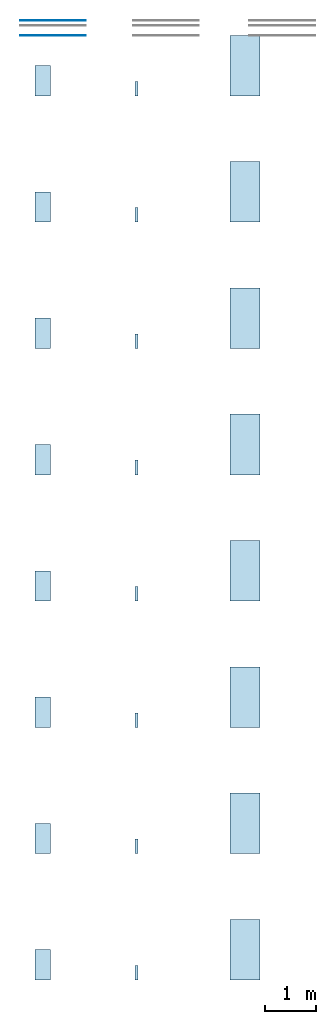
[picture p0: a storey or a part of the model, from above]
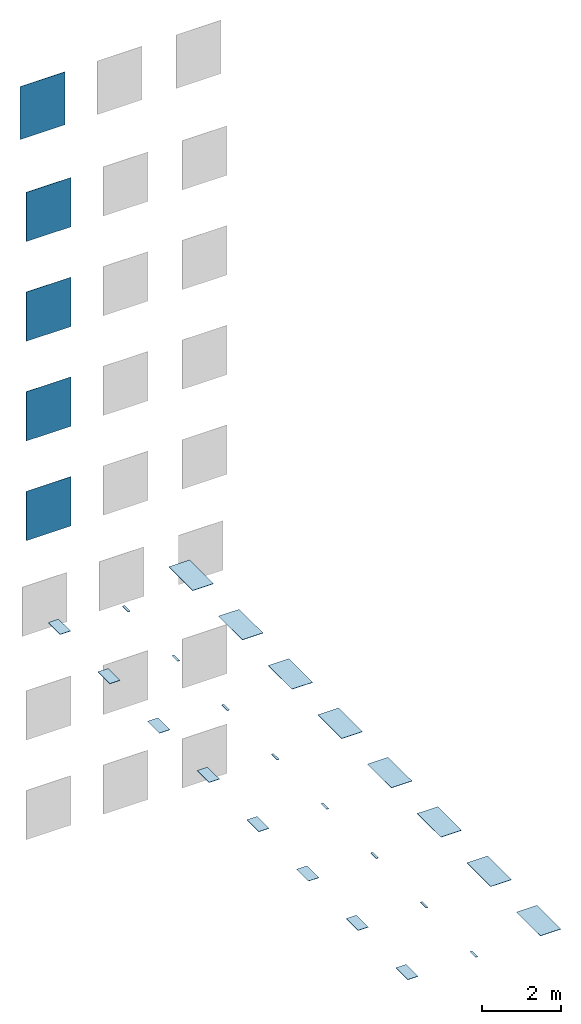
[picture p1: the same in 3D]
Properties of the parts of a building model (IFC2X3)

# File
Description: ViewDefinition [CoordinationView_V2.0], RevitIdentifiers [VersionGUID: be6d3f83-cdeb-4463-9c20-2c39ddd38491, NumberOfSaves: 313], CoordinateReference [CoordinateBase: Shared Coordinates, ProjectSite: Internal]
File name: Project Number
Time: 2025-01-29T16:04:23+01:00
Written by: ODA SDAI 24.3
Made in: Autodesk Revit 24.1.11.26 (ENU) - IFC 24.1.11.26

# IfcProject, Project Number
LongName: Refin-Blended; Phase: Project Status

# IfcSite, Default
RefLatitude: 51, 30, 0, 549316; RefLongitude: 0, -7, -34, -450321; RefElevation: 0 mm

# IfcBuilding
Pset_BuildingCommon - NumberOfStoreys: 1

# IfcBuildingStorey: Level:Circle Head - Project Datum (2)
Pset_AirSideSystemInformation - sets with these values: 2
Name | LongName = Name | Elevation (mm)
Level 0 | Level 0 | 0
Level 1 | Level 1 | 4000

# IfcSlab: Floor:Floor_Tiles_Refin-Upside-Black-30x60 RK33, Floor:Floor_Tiles_Refin-Upside-Black-30x60 RK33:304668
In: Level 0
Type - PredefinedType: FLOOR; Material: Upside-Black-30x60 RK33 9 mm, <Unnamed> 1 mm
Type - Pset_ConcreteElementGeneral - FireRating: INERT
Type - Pset_ElementShading - Color: BLACK
Type - Pset_FireRatingProperties - SurfaceSpreadOfFlame: INERT
Type - Pset_ManufacturerOccurrence - BarCode: N/A; SerialNumber: N/A
Type - Pset_ManufacturerTypeInformation - ArticleNumber: RK33; ModelReference: RK33; ModelLabel: BLACK R 30X60; Manufacturer: info@refin.it; ProductionYear: N/A
Type - Pset_PrecastConcreteElementGeneral - SerialNumber: N/A
Type - Pset_ProductRequirements - Name: Upside_Black_30X60 R; Category: Pr_35_93_96_19:Ceramic tiles
Type - Pset_QuantityTakeOff - Reference: N/A
Type - Pset_ReinforcementBarPitchOfSlab - Description: PORCELAIN STONEWARE TILE; Reference: N/A
Type - Pset_SlabCommon - Reference: N/A; IsExternal: no; AcousticRating: N/A; FireRating: INERT; SurfaceSpreadOfFlame: INERT
Type - Pset_Warranty - WarrantyContent: N/A; Exclusions: N/A
Pset_QuantityTakeOff - sets with these values: 2
Pset_SlabCommon - LoadBearing: no; PitchAngle: 0 deg

# IfcSlab: Floor:Floor_Tiles_Refin-Upside-Black-6,3x29 RK41, Floor:Floor_Tiles_Refin-Upside-Black-6,3x29 RK41:350442
In: Level 0
Type - PredefinedType: FLOOR; Material: Upside-Black-6,3x29 RK41 9 mm, <Unnamed> 1 mm
Type - Pset_ConcreteElementGeneral - FireRating: INERT
Type - Pset_ElementShading - Color: BLACK
Type - Pset_FireRatingProperties - SurfaceSpreadOfFlame: INERT
Type - Pset_ManufacturerOccurrence - BarCode: N/A; SerialNumber: N/A
Type - Pset_ManufacturerTypeInformation - ArticleNumber: RK41; ModelReference: RK41; ModelLabel: BLACK R 6,3X29; Manufacturer: info@refin.it; ProductionYear: N/A
Type - Pset_PrecastConcreteElementGeneral - SerialNumber: N/A
Type - Pset_ProductRequirements - Name: Upside_Black_6,3X29 R; Category: Pr_35_93_96_19:Ceramic tiles
Type - Pset_QuantityTakeOff - Reference: N/A
Type - Pset_ReinforcementBarPitchOfSlab - Description: PORCELAIN STONEWARE TILE; Reference: N/A
Type - Pset_SlabCommon - Reference: N/A; IsExternal: no; AcousticRating: N/A; FireRating: INERT; SurfaceSpreadOfFlame: INERT
Type - Pset_Warranty - WarrantyContent: N/A; Exclusions: N/A
Pset_QuantityTakeOff - sets with these values: 2
Pset_SlabCommon - LoadBearing: no; PitchAngle: 0 deg

# IfcSlab: Floor:Floor_Tiles_Refin-Upside-Black-60x120 RK25, Floor:Floor_Tiles_Refin-Upside-Black-60x120 RK25:350624
In: Level 0
Type - PredefinedType: FLOOR; Material: Upside-Black-60x120 RK25 9 mm, <Unnamed> 1 mm
Type - Pset_ConcreteElementGeneral - FireRating: INERT
Type - Pset_ElementShading - Color: BLACK
Type - Pset_FireRatingProperties - SurfaceSpreadOfFlame: INERT
Type - Pset_ManufacturerOccurrence - BarCode: N/A; SerialNumber: N/A
Type - Pset_ManufacturerTypeInformation - ArticleNumber: RK25; ModelReference: RK25; ModelLabel: BLACK R 60X120; Manufacturer: info@refin.it; ProductionYear: N/A
Type - Pset_PrecastConcreteElementGeneral - SerialNumber: N/A
Type - Pset_ProductRequirements - Name: Upside_Black_60X120 R; Category: Pr_35_93_96_19:Ceramic tiles
Type - Pset_QuantityTakeOff - Reference: N/A
Type - Pset_ReinforcementBarPitchOfSlab - Description: PORCELAIN STONEWARE TILE; Reference: N/A
Type - Pset_SlabCommon - Reference: N/A; IsExternal: no; AcousticRating: N/A; FireRating: INERT; SurfaceSpreadOfFlame: INERT
Type - Pset_Warranty - WarrantyContent: N/A; Exclusions: N/A
Pset_QuantityTakeOff - sets with these values: 2
Pset_SlabCommon - LoadBearing: no; PitchAngle: 0 deg

# IfcSlab: Floor:Floor_Tiles_Refin-Upside-Blue-30x60 RK34, Floor:Floor_Tiles_Refin-Upside-Blue-30x60 RK34:351193
In: Level 0
Type - PredefinedType: FLOOR; Material: Upside-Blue-30x60 RK34 9 mm, <Unnamed> 1 mm
Type - Pset_ConcreteElementGeneral - FireRating: INERT
Type - Pset_ElementShading - Color: BLUE
Type - Pset_FireRatingProperties - SurfaceSpreadOfFlame: INERT
Type - Pset_ManufacturerOccurrence - BarCode: N/A; SerialNumber: N/A
Type - Pset_ManufacturerTypeInformation - ArticleNumber: RK34; ModelReference: RK34; ModelLabel: BLUE R 30X60; Manufacturer: info@refin.it; ProductionYear: N/A
Type - Pset_PrecastConcreteElementGeneral - SerialNumber: N/A
Type - Pset_ProductRequirements - Name: Upside_Blue_30X60 R; Category: Pr_35_93_96_19:Ceramic tiles
Type - Pset_QuantityTakeOff - Reference: N/A
Type - Pset_ReinforcementBarPitchOfSlab - Description: PORCELAIN STONEWARE TILE; Reference: N/A
Type - Pset_SlabCommon - Reference: N/A; IsExternal: no; AcousticRating: N/A; FireRating: INERT; SurfaceSpreadOfFlame: INERT
Type - Pset_Warranty - WarrantyContent: N/A; Exclusions: N/A
Pset_QuantityTakeOff - sets with these values: 2
Pset_SlabCommon - LoadBearing: no; PitchAngle: 0 deg

# IfcSlab: Floor:Floor_Tiles_Refin-Upside-Blue-6,3x29 RK42, Floor:Floor_Tiles_Refin-Upside-Blue-6,3x29 RK42:351201
In: Level 0
Type - PredefinedType: FLOOR; Material: Upside-Blue-6,3x29 RK42 9 mm, <Unnamed> 1 mm
Type - Pset_ConcreteElementGeneral - FireRating: INERT
Type - Pset_ElementShading - Color: BLUE
Type - Pset_FireRatingProperties - SurfaceSpreadOfFlame: INERT
Type - Pset_ManufacturerOccurrence - BarCode: N/A; SerialNumber: N/A
Type - Pset_ManufacturerTypeInformation - ArticleNumber: RK42; ModelReference: RK42; ModelLabel: BLUE R 6,3X29; Manufacturer: info@refin.it; ProductionYear: N/A
Type - Pset_PrecastConcreteElementGeneral - SerialNumber: N/A
Type - Pset_ProductRequirements - Name: Upside_Blue_6,3X29 R; Category: Pr_35_93_96_19:Ceramic tiles
Type - Pset_QuantityTakeOff - Reference: N/A
Type - Pset_ReinforcementBarPitchOfSlab - Description: PORCELAIN STONEWARE TILE; Reference: N/A
Type - Pset_SlabCommon - Reference: N/A; IsExternal: no; AcousticRating: N/A; FireRating: INERT; SurfaceSpreadOfFlame: INERT
Type - Pset_Warranty - WarrantyContent: N/A; Exclusions: N/A
Pset_QuantityTakeOff - sets with these values: 2
Pset_SlabCommon - LoadBearing: no; PitchAngle: 0 deg

# IfcSlab: Floor:Floor_Tiles_Refin-Upside-Blue-60x120 RK26, Floor:Floor_Tiles_Refin-Upside-Blue-60x120 RK26:351209
In: Level 0
Type - PredefinedType: FLOOR; Material: Upside-Blue-60x120 RK26 9 mm, <Unnamed> 1 mm
Type - Pset_ConcreteElementGeneral - FireRating: INERT
Type - Pset_ElementShading - Color: BLUE
Type - Pset_FireRatingProperties - SurfaceSpreadOfFlame: INERT
Type - Pset_ManufacturerOccurrence - BarCode: N/A; SerialNumber: N/A
Type - Pset_ManufacturerTypeInformation - ArticleNumber: RK26; ModelReference: RK26; ModelLabel: BLUE R 60X120; Manufacturer: info@refin.it; ProductionYear: N/A
Type - Pset_PrecastConcreteElementGeneral - SerialNumber: N/A
Type - Pset_ProductRequirements - Name: Upside_Blue_60X120 R; Category: Pr_35_93_96_19:Ceramic tiles
Type - Pset_QuantityTakeOff - Reference: N/A
Type - Pset_ReinforcementBarPitchOfSlab - Description: PORCELAIN STONEWARE TILE; Reference: N/A
Type - Pset_SlabCommon - Reference: N/A; IsExternal: no; AcousticRating: N/A; FireRating: INERT; SurfaceSpreadOfFlame: INERT
Type - Pset_Warranty - WarrantyContent: N/A; Exclusions: N/A
Pset_QuantityTakeOff - sets with these values: 2
Pset_SlabCommon - LoadBearing: no; PitchAngle: 0 deg

# IfcSlab: Floor:Floor_Tiles_Refin-Upside-Green-30x60 RK35, Floor:Floor_Tiles_Refin-Upside-Green-30x60 RK35:351773
In: Level 0
Type - PredefinedType: FLOOR; Material: Upside-Green-30x60 RK35 9 mm, <Unnamed> 1 mm
Type - Pset_ConcreteElementGeneral - FireRating: INERT
Type - Pset_ElementShading - Color: GREEN
Type - Pset_FireRatingProperties - SurfaceSpreadOfFlame: INERT
Type - Pset_ManufacturerOccurrence - BarCode: N/A; SerialNumber: N/A
Type - Pset_ManufacturerTypeInformation - ArticleNumber: RK35; ModelReference: RK35; ModelLabel: GREEN R 30X60; Manufacturer: info@refin.it; ProductionYear: N/A
Type - Pset_PrecastConcreteElementGeneral - SerialNumber: N/A
Type - Pset_ProductRequirements - Name: Upside_Green_30X60 R; Category: Pr_35_93_96_19:Ceramic tiles
Type - Pset_QuantityTakeOff - Reference: N/A
Type - Pset_ReinforcementBarPitchOfSlab - Description: PORCELAIN STONEWARE TILE; Reference: N/A
Type - Pset_SlabCommon - Reference: N/A; IsExternal: no; AcousticRating: N/A; FireRating: INERT; SurfaceSpreadOfFlame: INERT
Type - Pset_Warranty - WarrantyContent: N/A; Exclusions: N/A
Pset_QuantityTakeOff - sets with these values: 2
Pset_SlabCommon - LoadBearing: no; PitchAngle: 0 deg

# IfcSlab: Floor:Floor_Tiles_Refin-Upside-Green-6,3x29 RK43, Floor:Floor_Tiles_Refin-Upside-Green-6,3x29 RK43:351781
In: Level 0
Type - PredefinedType: FLOOR; Material: Upside-Green-6,3x29 RK43 9 mm, <Unnamed> 1 mm
Type - Pset_ConcreteElementGeneral - FireRating: INERT
Type - Pset_ElementShading - Color: GREEN
Type - Pset_FireRatingProperties - SurfaceSpreadOfFlame: INERT
Type - Pset_ManufacturerOccurrence - BarCode: N/A; SerialNumber: N/A
Type - Pset_ManufacturerTypeInformation - ArticleNumber: RK43; ModelReference: RK43; ModelLabel: GREEN R 6,3X29; Manufacturer: info@refin.it; ProductionYear: N/A
Type - Pset_PrecastConcreteElementGeneral - SerialNumber: N/A
Type - Pset_ProductRequirements - Name: Upside_Green_6,3X29 R; Category: Pr_35_93_96_19:Ceramic tiles
Type - Pset_QuantityTakeOff - Reference: N/A
Type - Pset_ReinforcementBarPitchOfSlab - Description: PORCELAIN STONEWARE TILE; Reference: N/A
Type - Pset_SlabCommon - Reference: N/A; IsExternal: no; AcousticRating: N/A; FireRating: INERT; SurfaceSpreadOfFlame: INERT
Type - Pset_Warranty - WarrantyContent: N/A; Exclusions: N/A
Pset_QuantityTakeOff - sets with these values: 2
Pset_SlabCommon - LoadBearing: no; PitchAngle: 0 deg

# IfcSlab: Floor:Floor_Tiles_Refin-Upside-Green-60x120 RK27, Floor:Floor_Tiles_Refin-Upside-Green-60x120 RK27:351789
In: Level 0
Type - PredefinedType: FLOOR; Material: Upside-Green-60x120 RK27 9 mm, <Unnamed> 1 mm
Type - Pset_ConcreteElementGeneral - FireRating: INERT
Type - Pset_ElementShading - Color: GREEN
Type - Pset_FireRatingProperties - SurfaceSpreadOfFlame: INERT
Type - Pset_ManufacturerOccurrence - BarCode: N/A; SerialNumber: N/A
Type - Pset_ManufacturerTypeInformation - ArticleNumber: RK27; ModelReference: RK27; ModelLabel: GREEN R 60X120; Manufacturer: info@refin.it; ProductionYear: N/A
Type - Pset_PrecastConcreteElementGeneral - SerialNumber: N/A
Type - Pset_ProductRequirements - Name: Upside_Green_60X120 R; Category: Pr_35_93_96_19:Ceramic tiles
Type - Pset_QuantityTakeOff - Reference: N/A
Type - Pset_ReinforcementBarPitchOfSlab - Description: PORCELAIN STONEWARE TILE; Reference: N/A
Type - Pset_SlabCommon - Reference: N/A; IsExternal: no; AcousticRating: N/A; FireRating: INERT; SurfaceSpreadOfFlame: INERT
Type - Pset_Warranty - WarrantyContent: N/A; Exclusions: N/A
Pset_QuantityTakeOff - sets with these values: 2
Pset_SlabCommon - LoadBearing: no; PitchAngle: 0 deg

# IfcSlab: Floor:Floor_Tiles_Refin-Upside-Pink-30x60 RK37, Floor:Floor_Tiles_Refin-Upside-Pink-30x60 RK37:352848
In: Level 0
Type - PredefinedType: FLOOR; Material: Upside-Pink-30x60 RK37 9 mm, <Unnamed> 1 mm
Type - Pset_ConcreteElementGeneral - FireRating: INERT
Type - Pset_ElementShading - Color: PINK
Type - Pset_FireRatingProperties - SurfaceSpreadOfFlame: INERT
Type - Pset_ManufacturerOccurrence - BarCode: N/A; SerialNumber: N/A
Type - Pset_ManufacturerTypeInformation - ArticleNumber: RK37; ModelReference: RK37; ModelLabel: PINK R 30X60; Manufacturer: info@refin.it; ProductionYear: N/A
Type - Pset_PrecastConcreteElementGeneral - SerialNumber: N/A
Type - Pset_ProductRequirements - Name: Upside_Pink_30X60 R; Category: Pr_35_93_96_19:Ceramic tiles
Type - Pset_QuantityTakeOff - Reference: N/A
Type - Pset_ReinforcementBarPitchOfSlab - Description: PORCELAIN STONEWARE TILE; Reference: N/A
Type - Pset_SlabCommon - Reference: N/A; IsExternal: no; AcousticRating: N/A; FireRating: INERT; SurfaceSpreadOfFlame: INERT
Type - Pset_Warranty - WarrantyContent: N/A; Exclusions: N/A
Pset_QuantityTakeOff - sets with these values: 2
Pset_SlabCommon - LoadBearing: no; PitchAngle: 0 deg

# IfcSlab: Floor:Floor_Tiles_Refin-Upside-Pink-6,3x29 RK45, Floor:Floor_Tiles_Refin-Upside-Pink-6,3x29 RK45:352856
In: Level 0
Type - PredefinedType: FLOOR; Material: Upside-Pink-6,3x29 RK45 9 mm, <Unnamed> 1 mm
Type - Pset_ConcreteElementGeneral - FireRating: INERT
Type - Pset_ElementShading - Color: PINK
Type - Pset_FireRatingProperties - SurfaceSpreadOfFlame: INERT
Type - Pset_ManufacturerOccurrence - BarCode: N/A; SerialNumber: N/A
Type - Pset_ManufacturerTypeInformation - ArticleNumber: RK45; ModelReference: RK45; ModelLabel: PINK R 6,3X29; Manufacturer: info@refin.it; ProductionYear: N/A
Type - Pset_PrecastConcreteElementGeneral - SerialNumber: N/A
Type - Pset_ProductRequirements - Name: Upside_Pink_6,3X29 R; Category: Pr_35_93_96_19:Ceramic tiles
Type - Pset_QuantityTakeOff - Reference: N/A
Type - Pset_ReinforcementBarPitchOfSlab - Description: PORCELAIN STONEWARE TILE; Reference: N/A
Type - Pset_SlabCommon - Reference: N/A; IsExternal: no; AcousticRating: N/A; FireRating: INERT; SurfaceSpreadOfFlame: INERT
Type - Pset_Warranty - WarrantyContent: N/A; Exclusions: N/A
Pset_QuantityTakeOff - sets with these values: 2
Pset_SlabCommon - LoadBearing: no; PitchAngle: 0 deg

# IfcSlab: Floor:Floor_Tiles_Refin-Upside-Pink-60x120 RK29, Floor:Floor_Tiles_Refin-Upside-Pink-60x120 RK29:352863
In: Level 0
Type - PredefinedType: FLOOR; Material: Upside-Pink-60x120 RK29 9 mm, <Unnamed> 1 mm
Type - Pset_ConcreteElementGeneral - FireRating: INERT
Type - Pset_ElementShading - Color: PINK
Type - Pset_FireRatingProperties - SurfaceSpreadOfFlame: INERT
Type - Pset_ManufacturerOccurrence - BarCode: N/A; SerialNumber: N/A
Type - Pset_ManufacturerTypeInformation - ArticleNumber: RK29; ModelReference: RK29; ModelLabel: PINK R 60X120; Manufacturer: info@refin.it; ProductionYear: N/A
Type - Pset_PrecastConcreteElementGeneral - SerialNumber: N/A
Type - Pset_ProductRequirements - Name: Upside_Pink_60X120 R; Category: Pr_35_93_96_19:Ceramic tiles
Type - Pset_QuantityTakeOff - Reference: N/A
Type - Pset_ReinforcementBarPitchOfSlab - Description: PORCELAIN STONEWARE TILE; Reference: N/A
Type - Pset_SlabCommon - Reference: N/A; IsExternal: no; AcousticRating: N/A; FireRating: INERT; SurfaceSpreadOfFlame: INERT
Type - Pset_Warranty - WarrantyContent: N/A; Exclusions: N/A
Pset_QuantityTakeOff - sets with these values: 2
Pset_SlabCommon - LoadBearing: no; PitchAngle: 0 deg

# IfcSlab: Floor:Floor_Tiles_Refin-Upside-Red-30x60 RK38, Floor:Floor_Tiles_Refin-Upside-Red-30x60 RK38:353682
In: Level 0
Type - PredefinedType: FLOOR; Material: Upside-Red-30x60 RK38 9 mm, <Unnamed> 1 mm
Type - Pset_ConcreteElementGeneral - FireRating: INERT
Type - Pset_ElementShading - Color: RED
Type - Pset_FireRatingProperties - SurfaceSpreadOfFlame: INERT
Type - Pset_ManufacturerOccurrence - BarCode: N/A; SerialNumber: N/A
Type - Pset_ManufacturerTypeInformation - ArticleNumber: RK38; ModelReference: RK38; ModelLabel: RED R 30X60; Manufacturer: info@refin.it; ProductionYear: N/A
Type - Pset_PrecastConcreteElementGeneral - SerialNumber: N/A
Type - Pset_ProductRequirements - Name: Upside_Red_30X60 R; Category: Pr_35_93_96_19:Ceramic tiles
Type - Pset_QuantityTakeOff - Reference: N/A
Type - Pset_ReinforcementBarPitchOfSlab - Description: PORCELAIN STONEWARE TILE; Reference: N/A
Type - Pset_SlabCommon - Reference: N/A; IsExternal: no; AcousticRating: N/A; FireRating: INERT; SurfaceSpreadOfFlame: INERT
Type - Pset_Warranty - WarrantyContent: N/A; Exclusions: N/A
Pset_QuantityTakeOff - sets with these values: 2
Pset_SlabCommon - LoadBearing: no; PitchAngle: 0 deg

# IfcSlab: Floor:Floor_Tiles_Refin-Upside-Red-6,3x29 RK46, Floor:Floor_Tiles_Refin-Upside-Red-6,3x29 RK46:353690
In: Level 0
Type - PredefinedType: FLOOR; Material: Upside-Red-6,3x29 RK46 9 mm, <Unnamed> 1 mm
Type - Pset_ConcreteElementGeneral - FireRating: INERT
Type - Pset_ElementShading - Color: RED
Type - Pset_FireRatingProperties - SurfaceSpreadOfFlame: INERT
Type - Pset_ManufacturerOccurrence - BarCode: N/A; SerialNumber: N/A
Type - Pset_ManufacturerTypeInformation - ArticleNumber: RK46; ModelReference: RK46; ModelLabel: RED R 6,3X29; Manufacturer: info@refin.it; ProductionYear: N/A
Type - Pset_PrecastConcreteElementGeneral - SerialNumber: N/A
Type - Pset_ProductRequirements - Name: Upside_Red_6,3X29 R; Category: Pr_35_93_96_19:Ceramic tiles
Type - Pset_QuantityTakeOff - Reference: N/A
Type - Pset_ReinforcementBarPitchOfSlab - Description: PORCELAIN STONEWARE TILE; Reference: N/A
Type - Pset_SlabCommon - Reference: N/A; IsExternal: no; AcousticRating: N/A; FireRating: INERT; SurfaceSpreadOfFlame: INERT
Type - Pset_Warranty - WarrantyContent: N/A; Exclusions: N/A
Pset_QuantityTakeOff - sets with these values: 2
Pset_SlabCommon - LoadBearing: no; PitchAngle: 0 deg

# IfcSlab: Floor:Floor_Tiles_Refin-Upside-Red-60x120 RK30, Floor:Floor_Tiles_Refin-Upside-Red-60x120 RK30:353697
In: Level 0
Type - PredefinedType: FLOOR; Material: Upside-Red-60x120 RK30 9 mm, <Unnamed> 1 mm
Type - Pset_ConcreteElementGeneral - FireRating: INERT
Type - Pset_ElementShading - Color: RED
Type - Pset_FireRatingProperties - SurfaceSpreadOfFlame: INERT
Type - Pset_ManufacturerOccurrence - BarCode: N/A; SerialNumber: N/A
Type - Pset_ManufacturerTypeInformation - ArticleNumber: RK30; ModelReference: RK30; ModelLabel: RED R 60X120; Manufacturer: info@refin.it; ProductionYear: N/A
Type - Pset_PrecastConcreteElementGeneral - SerialNumber: N/A
Type - Pset_ProductRequirements - Name: Upside_Red_60X120 R; Category: Pr_35_93_96_19:Ceramic tiles
Type - Pset_QuantityTakeOff - Reference: N/A
Type - Pset_ReinforcementBarPitchOfSlab - Description: PORCELAIN STONEWARE TILE; Reference: N/A
Type - Pset_SlabCommon - Reference: N/A; IsExternal: no; AcousticRating: N/A; FireRating: INERT; SurfaceSpreadOfFlame: INERT
Type - Pset_Warranty - WarrantyContent: N/A; Exclusions: N/A
Pset_QuantityTakeOff - sets with these values: 2
Pset_SlabCommon - LoadBearing: no; PitchAngle: 0 deg

# IfcSlab: Floor:Floor_Tiles_Refin-Upside-Sky-30x60 RK39, Floor:Floor_Tiles_Refin-Upside-Sky-30x60 RK39:354499
In: Level 0
Type - PredefinedType: FLOOR; Material: Upside-Sky-30x60 RK39 9 mm, <Unnamed> 1 mm
Type - Pset_ConcreteElementGeneral - FireRating: INERT
Type - Pset_ElementShading - Color: LIGHT BLUE
Type - Pset_FireRatingProperties - SurfaceSpreadOfFlame: INERT
Type - Pset_ManufacturerOccurrence - BarCode: N/A; SerialNumber: N/A
Type - Pset_ManufacturerTypeInformation - ArticleNumber: RK39; ModelReference: RK39; ModelLabel: SKY R 30X60; Manufacturer: info@refin.it; ProductionYear: N/A
Type - Pset_PrecastConcreteElementGeneral - SerialNumber: N/A
Type - Pset_ProductRequirements - Name: Upside_Sky_30X60 R; Category: Pr_35_93_96_19:Ceramic tiles
Type - Pset_QuantityTakeOff - Reference: N/A
Type - Pset_ReinforcementBarPitchOfSlab - Description: PORCELAIN STONEWARE TILE; Reference: N/A
Type - Pset_SlabCommon - Reference: N/A; IsExternal: no; AcousticRating: N/A; FireRating: INERT; SurfaceSpreadOfFlame: INERT
Type - Pset_Warranty - WarrantyContent: N/A; Exclusions: N/A
Pset_QuantityTakeOff - sets with these values: 2
Pset_SlabCommon - LoadBearing: no; PitchAngle: 0 deg

# IfcSlab: Floor:Floor_Tiles_Refin-Upside-Sky-6,3x29 RK47, Floor:Floor_Tiles_Refin-Upside-Sky-6,3x29 RK47:354507
In: Level 0
Type - PredefinedType: FLOOR; Material: Upside-Sky-6,3x29 RK47 9 mm, <Unnamed> 1 mm
Type - Pset_ConcreteElementGeneral - FireRating: INERT
Type - Pset_ElementShading - Color: LIGHT BLUE
Type - Pset_FireRatingProperties - SurfaceSpreadOfFlame: INERT
Type - Pset_ManufacturerOccurrence - BarCode: N/A; SerialNumber: N/A
Type - Pset_ManufacturerTypeInformation - ArticleNumber: RK47; ModelReference: RK47; ModelLabel: SKY R 6,3X29; Manufacturer: info@refin.it; ProductionYear: N/A
Type - Pset_PrecastConcreteElementGeneral - SerialNumber: N/A
Type - Pset_ProductRequirements - Name: Upside_Sky_6,3X29 R; Category: Pr_35_93_96_19:Ceramic tiles
Type - Pset_QuantityTakeOff - Reference: N/A
Type - Pset_ReinforcementBarPitchOfSlab - Description: PORCELAIN STONEWARE TILE; Reference: N/A
Type - Pset_SlabCommon - Reference: N/A; IsExternal: no; AcousticRating: N/A; FireRating: INERT; SurfaceSpreadOfFlame: INERT
Type - Pset_Warranty - WarrantyContent: N/A; Exclusions: N/A
Pset_QuantityTakeOff - sets with these values: 2
Pset_SlabCommon - LoadBearing: no; PitchAngle: 0 deg

# IfcSlab: Floor:Floor_Tiles_Refin-Upside-Sky-60x120 RK31, Floor:Floor_Tiles_Refin-Upside-Sky-60x120 RK31:354514
In: Level 0
Type - PredefinedType: FLOOR; Material: Upside-Sky-60x120 RK31 9 mm, <Unnamed> 1 mm
Type - Pset_ConcreteElementGeneral - FireRating: INERT
Type - Pset_ElementShading - Color: LIGHT BLUE
Type - Pset_FireRatingProperties - SurfaceSpreadOfFlame: INERT
Type - Pset_ManufacturerOccurrence - BarCode: N/A; SerialNumber: N/A
Type - Pset_ManufacturerTypeInformation - ArticleNumber: RK31; ModelReference: RK31; ModelLabel: SKY R 60X120; Manufacturer: info@refin.it; ProductionYear: N/A
Type - Pset_PrecastConcreteElementGeneral - SerialNumber: N/A
Type - Pset_ProductRequirements - Name: Upside_Sky_60X120 R; Category: Pr_35_93_96_19:Ceramic tiles
Type - Pset_QuantityTakeOff - Reference: N/A
Type - Pset_ReinforcementBarPitchOfSlab - Description: PORCELAIN STONEWARE TILE; Reference: N/A
Type - Pset_SlabCommon - Reference: N/A; IsExternal: no; AcousticRating: N/A; FireRating: INERT; SurfaceSpreadOfFlame: INERT
Type - Pset_Warranty - WarrantyContent: N/A; Exclusions: N/A
Pset_QuantityTakeOff - sets with these values: 2
Pset_SlabCommon - LoadBearing: no; PitchAngle: 0 deg

# IfcSlab: Floor:Floor_Tiles_Refin-Upside-White-30x60 RK40, Floor:Floor_Tiles_Refin-Upside-White-30x60 RK40:355247
In: Level 0
Type - PredefinedType: FLOOR; Material: Upside-White-30x60 RK40 9 mm, <Unnamed> 1 mm
Type - Pset_ConcreteElementGeneral - FireRating: INERT
Type - Pset_ElementShading - Color: WHITE
Type - Pset_FireRatingProperties - SurfaceSpreadOfFlame: INERT
Type - Pset_ManufacturerOccurrence - BarCode: N/A; SerialNumber: N/A
Type - Pset_ManufacturerTypeInformation - ArticleNumber: RK40; ModelReference: RK40; ModelLabel: WHITE R 30X60; Manufacturer: info@refin.it; ProductionYear: N/A
Type - Pset_PrecastConcreteElementGeneral - SerialNumber: N/A
Type - Pset_ProductRequirements - Name: Upside_White_30X60 R; Category: Pr_35_93_96_19:Ceramic tiles
Type - Pset_QuantityTakeOff - Reference: N/A
Type - Pset_ReinforcementBarPitchOfSlab - Description: PORCELAIN STONEWARE TILE; Reference: N/A
Type - Pset_SlabCommon - Reference: N/A; IsExternal: no; AcousticRating: N/A; FireRating: INERT; SurfaceSpreadOfFlame: INERT
Type - Pset_Warranty - WarrantyContent: N/A; Exclusions: N/A
Pset_QuantityTakeOff - sets with these values: 2
Pset_SlabCommon - LoadBearing: no; PitchAngle: 0 deg

# IfcSlab: Floor:Floor_Tiles_Refin-Upside-White-6,3x29 RK48, Floor:Floor_Tiles_Refin-Upside-White-6,3x29 RK48:355255
In: Level 0
Type - PredefinedType: FLOOR; Material: Upside-White-6,3x29 RK48 9 mm, <Unnamed> 1 mm
Type - Pset_ConcreteElementGeneral - FireRating: INERT
Type - Pset_ElementShading - Color: WHITE
Type - Pset_FireRatingProperties - SurfaceSpreadOfFlame: INERT
Type - Pset_ManufacturerOccurrence - BarCode: N/A; SerialNumber: N/A
Type - Pset_ManufacturerTypeInformation - ArticleNumber: RK48; ModelReference: RK48; ModelLabel: WHITE R 6,3X29; Manufacturer: info@refin.it; ProductionYear: N/A
Type - Pset_PrecastConcreteElementGeneral - SerialNumber: N/A
Type - Pset_ProductRequirements - Name: Upside_White_6,3X29 R; Category: Pr_35_93_96_19:Ceramic tiles
Type - Pset_QuantityTakeOff - Reference: N/A
Type - Pset_ReinforcementBarPitchOfSlab - Description: PORCELAIN STONEWARE TILE; Reference: N/A
Type - Pset_SlabCommon - Reference: N/A; IsExternal: no; AcousticRating: N/A; FireRating: INERT; SurfaceSpreadOfFlame: INERT
Type - Pset_Warranty - WarrantyContent: N/A; Exclusions: N/A
Pset_QuantityTakeOff - sets with these values: 2
Pset_SlabCommon - LoadBearing: no; PitchAngle: 0 deg

# IfcSlab: Floor:Floor_Tiles_Refin-Upside-White-60x120 RK32, Floor:Floor_Tiles_Refin-Upside-White-60x120 RK32:355262
In: Level 0
Type - PredefinedType: FLOOR; Material: Upside-White-60x120 RK32 9 mm, <Unnamed> 1 mm
Type - Pset_ConcreteElementGeneral - FireRating: INERT
Type - Pset_ElementShading - Color: WHITE
Type - Pset_FireRatingProperties - SurfaceSpreadOfFlame: INERT
Type - Pset_ManufacturerOccurrence - BarCode: N/A; SerialNumber: N/A
Type - Pset_ManufacturerTypeInformation - ArticleNumber: RK32; ModelReference: RK32; ModelLabel: WHITE R 60X120; Manufacturer: info@refin.it; ProductionYear: N/A
Type - Pset_PrecastConcreteElementGeneral - SerialNumber: N/A
Type - Pset_ProductRequirements - Name: Upside_White_60X120 R; Category: Pr_35_93_96_19:Ceramic tiles
Type - Pset_QuantityTakeOff - Reference: N/A
Type - Pset_ReinforcementBarPitchOfSlab - Description: PORCELAIN STONEWARE TILE; Reference: N/A
Type - Pset_SlabCommon - Reference: N/A; IsExternal: no; AcousticRating: N/A; FireRating: INERT; SurfaceSpreadOfFlame: INERT
Type - Pset_Warranty - WarrantyContent: N/A; Exclusions: N/A
Pset_QuantityTakeOff - sets with these values: 2
Pset_SlabCommon - LoadBearing: no; PitchAngle: 0 deg

# IfcSlab: Floor:Floor_Tiles_Refin-Upside-Yellow-30x60 RK36, Floor:Floor_Tiles_Refin-Upside-Yellow-30x60 RK36:356125
In: Level 0
Type - PredefinedType: FLOOR; Material: Upside-Yellow-30x60 RK36 9 mm, <Unnamed> 1 mm
Type - Pset_ConcreteElementGeneral - FireRating: INERT
Type - Pset_ElementShading - Color: YELLOW
Type - Pset_FireRatingProperties - SurfaceSpreadOfFlame: INERT
Type - Pset_ManufacturerOccurrence - BarCode: N/A; SerialNumber: N/A
Type - Pset_ManufacturerTypeInformation - ArticleNumber: RK36; ModelReference: RK36; ModelLabel: YELLOW R 30X60; Manufacturer: info@refin.it; ProductionYear: N/A
Type - Pset_PrecastConcreteElementGeneral - SerialNumber: N/A
Type - Pset_ProductRequirements - Name: Upside_Yellow_30X60 R; Category: Pr_35_93_96_19:Ceramic tiles
Type - Pset_QuantityTakeOff - Reference: N/A
Type - Pset_ReinforcementBarPitchOfSlab - Description: PORCELAIN STONEWARE TILE; Reference: N/A
Type - Pset_SlabCommon - Reference: N/A; IsExternal: no; AcousticRating: N/A; FireRating: INERT; SurfaceSpreadOfFlame: INERT
Type - Pset_Warranty - WarrantyContent: N/A; Exclusions: N/A
Pset_QuantityTakeOff - sets with these values: 2
Pset_SlabCommon - LoadBearing: no; PitchAngle: 0 deg

# IfcSlab: Floor:Floor_Tiles_Refin-Upside-Yellow-6,3x29 RK44, Floor:Floor_Tiles_Refin-Upside-Yellow-6,3x29 RK44:356133
In: Level 0
Type - PredefinedType: FLOOR; Material: Upside-Yellow-6,3x29 RK44 9 mm, <Unnamed> 1 mm
Type - Pset_ConcreteElementGeneral - FireRating: INERT
Type - Pset_ElementShading - Color: YELLOW
Type - Pset_FireRatingProperties - SurfaceSpreadOfFlame: INERT
Type - Pset_ManufacturerOccurrence - BarCode: N/A; SerialNumber: N/A
Type - Pset_ManufacturerTypeInformation - ArticleNumber: RK44; ModelReference: RK44; ModelLabel: YELLOW R 6,3X29; Manufacturer: info@refin.it; ProductionYear: N/A
Type - Pset_PrecastConcreteElementGeneral - SerialNumber: N/A
Type - Pset_ProductRequirements - Name: Upside_Yellow_6,3X29 R; Category: Pr_35_93_96_19:Ceramic tiles
Type - Pset_QuantityTakeOff - Reference: N/A
Type - Pset_ReinforcementBarPitchOfSlab - Description: PORCELAIN STONEWARE TILE; Reference: N/A
Type - Pset_SlabCommon - Reference: N/A; IsExternal: no; AcousticRating: N/A; FireRating: INERT; SurfaceSpreadOfFlame: INERT
Type - Pset_Warranty - WarrantyContent: N/A; Exclusions: N/A
Pset_QuantityTakeOff - sets with these values: 2
Pset_SlabCommon - LoadBearing: no; PitchAngle: 0 deg

# IfcSlab: Floor:Floor_Tiles_Refin-Upside-Yellow-60x120 RK28, Floor:Floor_Tiles_Refin-Upside-Yellow-60x120 RK28:356140
In: Level 0
Type - PredefinedType: FLOOR; Material: Upside-Yellow-60x120 RK28 9 mm, <Unnamed> 1 mm
Type - Pset_ConcreteElementGeneral - FireRating: INERT
Type - Pset_ElementShading - Color: YELLOW
Type - Pset_FireRatingProperties - SurfaceSpreadOfFlame: INERT
Type - Pset_ManufacturerOccurrence - BarCode: N/A; SerialNumber: N/A
Type - Pset_ManufacturerTypeInformation - ArticleNumber: RK28; ModelReference: RK28; ModelLabel: YELLOW R 60X120; Manufacturer: info@refin.it; ProductionYear: N/A
Type - Pset_PrecastConcreteElementGeneral - SerialNumber: N/A
Type - Pset_ProductRequirements - Name: Upside_Yellow_60X120 R; Category: Pr_35_93_96_19:Ceramic tiles
Type - Pset_QuantityTakeOff - Reference: N/A
Type - Pset_ReinforcementBarPitchOfSlab - Description: PORCELAIN STONEWARE TILE; Reference: N/A
Type - Pset_SlabCommon - Reference: N/A; IsExternal: no; AcousticRating: N/A; FireRating: INERT; SurfaceSpreadOfFlame: INERT
Type - Pset_Warranty - WarrantyContent: N/A; Exclusions: N/A
Pset_QuantityTakeOff - sets with these values: 2
Pset_SlabCommon - LoadBearing: no; PitchAngle: 0 deg

# IfcWallStandardCase: Basic Wall:Wall_Tiles_Refin-Upside-Black-30x60 RK33, Basic Wall:Wall_Tiles_Refin-Upside-Black-30x60 RK33:334895
In: Level 0
Type - PredefinedType: STANDARD; Material: <Unnamed> 1 mm, Upside-Black-30x60 RK33 9 mm
Type - Pset_ElementShading - Color: BLACK
Type - Pset_FireRatingProperties - SurfaceSpreadOfFlame: INERT
Type - Pset_ManufacturerOccurrence - BarCode: N/A; SerialNumber: N/A
Type - Pset_ManufacturerTypeInformation - ArticleNumber: RK33; ModelReference: RK33; ModelLabel: BLACK R 30X60; Manufacturer: info@refin.it; ProductionYear: N/A
Type - Pset_PrecastConcreteElementGeneral - SerialNumber: N/A
Type - Pset_ProductRequirements - Name: Upside_Black_30X60 R; Category: Pr_35_93_96_19:Ceramic tiles
Type - Pset_QuantityTakeOff - Reference: N/A
Type - Pset_ReinforcementBarPitchOfWall - Description: PORCELAIN STONEWARE TILE; Reference: N/A
Type - Pset_WallCommon - Reference: N/A; IsExternal: no; AcousticRating: N/A; SurfaceSpreadOfFlame: INERT
Type - Pset_Warranty - WarrantyContent: N/A; Exclusions: N/A
Pset_QuantityTakeOff - sets with these values: 2
Pset_WallCommon - LoadBearing: no; ExtendToStructure: no

# IfcWallStandardCase: Basic Wall:Wall_Tiles_Refin-Upside-Black-6,3x29 RK41, Basic Wall:Wall_Tiles_Refin-Upside-Black-6,3x29 RK41:333696
In: Level 0
Type - PredefinedType: STANDARD; Material: <Unnamed> 1 mm, Upside-Black-6,3x29 RK41 9 mm
Type - Pset_ElementShading - Color: BLACK
Type - Pset_FireRatingProperties - SurfaceSpreadOfFlame: INERT
Type - Pset_ManufacturerOccurrence - BarCode: N/A; SerialNumber: N/A
Type - Pset_ManufacturerTypeInformation - ArticleNumber: RK41; ModelReference: RK41; ModelLabel: BLACK R 6,3X29; Manufacturer: info@refin.it; ProductionYear: N/A
Type - Pset_PrecastConcreteElementGeneral - SerialNumber: N/A
Type - Pset_ProductRequirements - Name: Upside_Black_6,3X29 R; Category: Pr_35_93_96_19:Ceramic tiles
Type - Pset_QuantityTakeOff - Reference: N/A
Type - Pset_ReinforcementBarPitchOfWall - Description: PORCELAIN STONEWARE TILE; Reference: N/A
Type - Pset_WallCommon - Reference: N/A; IsExternal: no; AcousticRating: N/A; SurfaceSpreadOfFlame: INERT
Type - Pset_Warranty - WarrantyContent: N/A; Exclusions: N/A
Pset_QuantityTakeOff - sets with these values: 2
Pset_WallCommon - LoadBearing: no; ExtendToStructure: no

# IfcWallStandardCase: Basic Wall:Wall_Tiles_Refin-Upside-Black-60x120 RK25, Basic Wall:Wall_Tiles_Refin-Upside-Black-60x120 RK25:334553
In: Level 0
Type - PredefinedType: STANDARD; Material: <Unnamed> 1 mm, Upside-Black-60x120 RK25 9 mm
Type - Pset_ElementShading - Color: BLACK
Type - Pset_FireRatingProperties - SurfaceSpreadOfFlame: INERT
Type - Pset_ManufacturerOccurrence - BarCode: N/A; SerialNumber: N/A
Type - Pset_ManufacturerTypeInformation - ArticleNumber: RK25; ModelReference: RK25; ModelLabel: BLACK R 60X120; Manufacturer: info@refin.it; ProductionYear: N/A
Type - Pset_PrecastConcreteElementGeneral - SerialNumber: N/A
Type - Pset_ProductRequirements - Name: Upside_Black_60X120 R; Category: Pr_35_93_96_19:Ceramic tiles
Type - Pset_QuantityTakeOff - Reference: N/A
Type - Pset_ReinforcementBarPitchOfWall - Description: PORCELAIN STONEWARE TILE; Reference: N/A
Type - Pset_WallCommon - Reference: N/A; IsExternal: no; AcousticRating: N/A; SurfaceSpreadOfFlame: INERT
Type - Pset_Warranty - WarrantyContent: N/A; Exclusions: N/A
Pset_QuantityTakeOff - sets with these values: 2
Pset_WallCommon - LoadBearing: no; ExtendToStructure: no

# IfcWallStandardCase: Basic Wall:Wall_Tiles_Refin-Upside-Blue-30x60 RK34, Basic Wall:Wall_Tiles_Refin-Upside-Blue-30x60 RK34:335038
In: Level 0
Type - PredefinedType: STANDARD; Material: <Unnamed> 1 mm, Upside-Blue-30x60 RK34 9 mm
Type - Pset_ElementShading - Color: BLUE
Type - Pset_FireRatingProperties - SurfaceSpreadOfFlame: INERT
Type - Pset_ManufacturerOccurrence - BarCode: N/A; SerialNumber: N/A
Type - Pset_ManufacturerTypeInformation - ArticleNumber: RK34; ModelReference: RK34; ModelLabel: BLUE R 30X60; Manufacturer: info@refin.it; ProductionYear: N/A
Type - Pset_PrecastConcreteElementGeneral - SerialNumber: N/A
Type - Pset_ProductRequirements - Name: Upside_Blue_30X60 R; Category: Pr_35_93_96_19:Ceramic tiles
Type - Pset_QuantityTakeOff - Reference: N/A
Type - Pset_ReinforcementBarPitchOfWall - Description: PORCELAIN STONEWARE TILE; Reference: N/A
Type - Pset_WallCommon - Reference: N/A; IsExternal: no; AcousticRating: N/A; SurfaceSpreadOfFlame: INERT
Type - Pset_Warranty - WarrantyContent: N/A; Exclusions: N/A
Pset_QuantityTakeOff - sets with these values: 2
Pset_WallCommon - LoadBearing: no; ExtendToStructure: no

# IfcWallStandardCase: Basic Wall:Wall_Tiles_Refin-Upside-Blue-6,3x29 RK42, Basic Wall:Wall_Tiles_Refin-Upside-Blue-6,3x29 RK42:335490
In: Level 0
Type - PredefinedType: STANDARD; Material: <Unnamed> 1 mm, Upside-Blue-6,3x29 RK42 9 mm
Type - Pset_ElementShading - Color: BLUE
Type - Pset_FireRatingProperties - SurfaceSpreadOfFlame: INERT
Type - Pset_ManufacturerOccurrence - BarCode: N/A; SerialNumber: N/A
Type - Pset_ManufacturerTypeInformation - ArticleNumber: RK42; ModelReference: RK42; ModelLabel: BLUE R 6,3X29; Manufacturer: info@refin.it; ProductionYear: N/A
Type - Pset_PrecastConcreteElementGeneral - SerialNumber: N/A
Type - Pset_ProductRequirements - Name: Upside_Blue_6,3X29 R; Category: Pr_35_93_96_19:Ceramic tiles
Type - Pset_QuantityTakeOff - Reference: N/A
Type - Pset_ReinforcementBarPitchOfWall - Description: PORCELAIN STONEWARE TILE; Reference: N/A
Type - Pset_WallCommon - Reference: N/A; IsExternal: no; AcousticRating: N/A; SurfaceSpreadOfFlame: INERT
Type - Pset_Warranty - WarrantyContent: N/A; Exclusions: N/A
Pset_QuantityTakeOff - sets with these values: 2
Pset_WallCommon - LoadBearing: no; ExtendToStructure: no

# IfcWallStandardCase: Basic Wall:Wall_Tiles_Refin-Upside-Blue-60x120 RK26, Basic Wall:Wall_Tiles_Refin-Upside-Blue-60x120 RK26:335882
In: Level 0
Type - PredefinedType: STANDARD; Material: <Unnamed> 1 mm, Upside-Blue-60x120 RK26 9 mm
Type - Pset_ElementShading - Color: BLUE
Type - Pset_FireRatingProperties - SurfaceSpreadOfFlame: INERT
Type - Pset_ManufacturerOccurrence - BarCode: N/A; SerialNumber: N/A
Type - Pset_ManufacturerTypeInformation - ArticleNumber: RK26; ModelReference: RK26; ModelLabel: BLUE R 60X120; Manufacturer: info@refin.it; ProductionYear: N/A
Type - Pset_PrecastConcreteElementGeneral - SerialNumber: N/A
Type - Pset_ProductRequirements - Name: Upside_Blue_60X120 R; Category: Pr_35_93_96_19:Ceramic tiles
Type - Pset_QuantityTakeOff - Reference: N/A
Type - Pset_ReinforcementBarPitchOfWall - Description: PORCELAIN STONEWARE TILE; Reference: N/A
Type - Pset_WallCommon - Reference: N/A; IsExternal: no; AcousticRating: N/A; SurfaceSpreadOfFlame: INERT
Type - Pset_Warranty - WarrantyContent: N/A; Exclusions: N/A
Pset_QuantityTakeOff - sets with these values: 2
Pset_WallCommon - LoadBearing: no; ExtendToStructure: no

# IfcWallStandardCase: Basic Wall:Wall_Tiles_Refin-Upside-Green-30x60 RK35, Basic Wall:Wall_Tiles_Refin-Upside-Green-30x60 RK35:352136
In: Level 0
Type - PredefinedType: STANDARD; Material: <Unnamed> 1 mm, Upside-Green-30x60 RK35 9 mm
Type - Pset_ElementShading - Color: GREEN
Type - Pset_FireRatingProperties - SurfaceSpreadOfFlame: INERT
Type - Pset_ManufacturerOccurrence - BarCode: N/A; SerialNumber: N/A
Type - Pset_ManufacturerTypeInformation - ArticleNumber: RK35; ModelReference: RK35; ModelLabel: GREEN R 30X60; Manufacturer: info@refin.it; ProductionYear: N/A
Type - Pset_PrecastConcreteElementGeneral - SerialNumber: N/A
Type - Pset_ProductRequirements - Name: Upside_Green_30X60 R; Category: Pr_35_93_96_19:Ceramic tiles
Type - Pset_QuantityTakeOff - Reference: N/A
Type - Pset_ReinforcementBarPitchOfWall - Description: PORCELAIN STONEWARE TILE; Reference: N/A
Type - Pset_WallCommon - Reference: N/A; IsExternal: no; AcousticRating: N/A; SurfaceSpreadOfFlame: INERT
Type - Pset_Warranty - WarrantyContent: N/A; Exclusions: N/A
Pset_QuantityTakeOff - sets with these values: 2
Pset_WallCommon - LoadBearing: no; ExtendToStructure: no

# IfcWallStandardCase: Basic Wall:Wall_Tiles_Refin-Upside-Green-6,3x29 RK43, Basic Wall:Wall_Tiles_Refin-Upside-Green-6,3x29 RK43:352457
In: Level 0
Type - PredefinedType: STANDARD; Material: <Unnamed> 1 mm, Upside-Green-6,3x29 RK43 9 mm
Type - Pset_ElementShading - Color: GREEN
Type - Pset_FireRatingProperties - SurfaceSpreadOfFlame: INERT
Type - Pset_ManufacturerOccurrence - BarCode: N/A; SerialNumber: N/A
Type - Pset_ManufacturerTypeInformation - ArticleNumber: RK43; ModelReference: RK43; ModelLabel: GREEN R 6,3X29; Manufacturer: info@refin.it; ProductionYear: N/A
Type - Pset_PrecastConcreteElementGeneral - SerialNumber: N/A
Type - Pset_ProductRequirements - Name: Upside_Green_6,3X29 R; Category: Pr_35_93_96_19:Ceramic tiles
Type - Pset_QuantityTakeOff - Reference: N/A
Type - Pset_ReinforcementBarPitchOfWall - Description: PORCELAIN STONEWARE TILE; Reference: N/A
Type - Pset_WallCommon - Reference: N/A; IsExternal: no; AcousticRating: N/A; SurfaceSpreadOfFlame: INERT
Type - Pset_Warranty - WarrantyContent: N/A; Exclusions: N/A
Pset_QuantityTakeOff - sets with these values: 2
Pset_WallCommon - LoadBearing: no; ExtendToStructure: no

# IfcWallStandardCase: Basic Wall:Wall_Tiles_Refin-Upside-Green-60x120 RK27, Basic Wall:Wall_Tiles_Refin-Upside-Green-60x120 RK27:352698
In: Level 0
Type - PredefinedType: STANDARD; Material: <Unnamed> 1 mm, Upside-Green-60x120 RK27 9 mm
Type - Pset_ElementShading - Color: GREEN
Type - Pset_FireRatingProperties - SurfaceSpreadOfFlame: INERT
Type - Pset_ManufacturerOccurrence - BarCode: N/A; SerialNumber: N/A
Type - Pset_ManufacturerTypeInformation - ArticleNumber: RK2760x120 cmRK27RK27; ModelReference: RK27; ModelLabel: GREEN R 60X120; Manufacturer: info@refin.it; ProductionYear: N/A
Type - Pset_PrecastConcreteElementGeneral - SerialNumber: N/A
Type - Pset_ProductRequirements - Name: Upside_Green_60X120 R; Category: Pr_35_93_96_19:Ceramic tiles
Type - Pset_QuantityTakeOff - Reference: N/A
Type - Pset_ReinforcementBarPitchOfWall - Description: PORCELAIN STONEWARE TILE; Reference: N/A
Type - Pset_WallCommon - Reference: N/A; IsExternal: no; AcousticRating: N/A; SurfaceSpreadOfFlame: INERT
Type - Pset_Warranty - WarrantyContent: N/A; Exclusions: N/A
Pset_QuantityTakeOff - sets with these values: 2
Pset_WallCommon - LoadBearing: no; ExtendToStructure: no

# IfcWallStandardCase: Basic Wall:Wall_Tiles_Refin-Upside-Pink-30x60 RK37, Basic Wall:Wall_Tiles_Refin-Upside-Pink-30x60 RK37:352939
In: Level 0
Type - PredefinedType: STANDARD; Material: <Unnamed> 1 mm, Upside-Pink-30x60 RK37 9 mm
Type - Pset_ElementShading - Color: PINK
Type - Pset_FireRatingProperties - SurfaceSpreadOfFlame: INERT
Type - Pset_ManufacturerOccurrence - BarCode: N/A; SerialNumber: N/A
Type - Pset_ManufacturerTypeInformation - ArticleNumber: RK37; ModelReference: RK37; ModelLabel: PINK R 30X60; Manufacturer: info@refin.it; ProductionYear: N/A
Type - Pset_PrecastConcreteElementGeneral - SerialNumber: N/A
Type - Pset_ProductRequirements - Name: Upside_Pink_30X60 R; Category: Pr_35_93_96_19:Ceramic tiles
Type - Pset_QuantityTakeOff - Reference: N/A
Type - Pset_ReinforcementBarPitchOfWall - Description: PORCELAIN STONEWARE TILE; Reference: N/A
Type - Pset_WallCommon - Reference: N/A; IsExternal: no; AcousticRating: N/A; SurfaceSpreadOfFlame: INERT
Type - Pset_Warranty - WarrantyContent: N/A; Exclusions: N/A
Pset_QuantityTakeOff - sets with these values: 2
Pset_WallCommon - LoadBearing: no; ExtendToStructure: no

# IfcWallStandardCase: Basic Wall:Wall_Tiles_Refin-Upside-Pink-6,3x29 RK45, Basic Wall:Wall_Tiles_Refin-Upside-Pink-6,3x29 RK45:353225
In: Level 0
Type - PredefinedType: STANDARD; Material: <Unnamed> 1 mm, Upside-Pink-6,3x29 RK45 9 mm
Type - Pset_ElementShading - Color: PINK
Type - Pset_FireRatingProperties - SurfaceSpreadOfFlame: INERT
Type - Pset_ManufacturerOccurrence - BarCode: N/A; SerialNumber: N/A
Type - Pset_ManufacturerTypeInformation - ArticleNumber: RK45; ModelReference: RK45; ModelLabel: PINK R 6,3X29; Manufacturer: info@refin.it; ProductionYear: N/A
Type - Pset_PrecastConcreteElementGeneral - SerialNumber: N/A
Type - Pset_ProductRequirements - Name: Upside_Pink_6,3X29 R; Category: Pr_35_93_96_19:Ceramic tiles
Type - Pset_QuantityTakeOff - Reference: N/A
Type - Pset_ReinforcementBarPitchOfWall - Description: PORCELAIN STONEWARE TILE; Reference: N/A
Type - Pset_WallCommon - Reference: N/A; IsExternal: no; AcousticRating: N/A; SurfaceSpreadOfFlame: INERT
Type - Pset_Warranty - WarrantyContent: N/A; Exclusions: N/A
Pset_QuantityTakeOff - sets with these values: 2
Pset_WallCommon - LoadBearing: no; ExtendToStructure: no

# IfcWallStandardCase: Basic Wall:Wall_Tiles_Refin-Upside-Pink-60x120 RK29, Basic Wall:Wall_Tiles_Refin-Upside-Pink-60x120 RK29:353487
In: Level 0
Type - PredefinedType: STANDARD; Material: <Unnamed> 1 mm, Upside-Pink-60x120 RK29 9 mm
Type - Pset_ElementShading - Color: PINK
Type - Pset_FireRatingProperties - SurfaceSpreadOfFlame: INERT
Type - Pset_ManufacturerOccurrence - BarCode: N/A; SerialNumber: N/A
Type - Pset_ManufacturerTypeInformation - ArticleNumber: RK29; ModelReference: RK29; ModelLabel: PINK R 60X120; Manufacturer: info@refin.it; ProductionYear: N/A
Type - Pset_PrecastConcreteElementGeneral - SerialNumber: N/A
Type - Pset_ProductRequirements - Name: Upside_Pink_60X120 R; Category: Pr_35_93_96_19:Ceramic tiles
Type - Pset_QuantityTakeOff - Reference: N/A
Type - Pset_ReinforcementBarPitchOfWall - Description: PORCELAIN STONEWARE TILE; Reference: N/A
Type - Pset_WallCommon - Reference: N/A; IsExternal: no; AcousticRating: N/A; SurfaceSpreadOfFlame: INERT
Type - Pset_Warranty - WarrantyContent: N/A; Exclusions: N/A
Pset_QuantityTakeOff - sets with these values: 2
Pset_WallCommon - LoadBearing: no; ExtendToStructure: no

# IfcWallStandardCase: Basic Wall:Wall_Tiles_Refin-Upside-Red-30x60 RK38, Basic Wall:Wall_Tiles_Refin-Upside-Red-30x60 RK38:353833
In: Level 0
Type - PredefinedType: STANDARD; Material: <Unnamed> 1 mm, Upside-Red-30x60 RK38 9 mm
Type - Pset_ElementShading - Color: RED
Type - Pset_FireRatingProperties - SurfaceSpreadOfFlame: INERT
Type - Pset_ManufacturerOccurrence - BarCode: N/A; SerialNumber: N/A
Type - Pset_ManufacturerTypeInformation - ArticleNumber: RK38; ModelReference: RK38; ModelLabel: RED R 30X60; Manufacturer: info@refin.it; ProductionYear: N/A
Type - Pset_PrecastConcreteElementGeneral - SerialNumber: N/A
Type - Pset_ProductRequirements - Name: Upside_Red_30X60 R; Category: Pr_35_93_96_19:Ceramic tiles
Type - Pset_QuantityTakeOff - Reference: N/A
Type - Pset_ReinforcementBarPitchOfWall - Description: PORCELAIN STONEWARE TILE; Reference: N/A
Type - Pset_WallCommon - Reference: N/A; IsExternal: no; AcousticRating: N/A; SurfaceSpreadOfFlame: INERT
Type - Pset_Warranty - WarrantyContent: N/A; Exclusions: N/A
Pset_QuantityTakeOff - sets with these values: 2
Pset_WallCommon - LoadBearing: no; ExtendToStructure: no

# IfcWallStandardCase: Basic Wall:Wall_Tiles_Refin-Upside-Red-6,3x29 RK46, Basic Wall:Wall_Tiles_Refin-Upside-Red-6,3x29 RK46:354129
In: Level 0
Type - PredefinedType: STANDARD; Material: <Unnamed> 1 mm, Upside-Red-6,3x29 RK46 9 mm
Type - Pset_ElementShading - Color: RED
Type - Pset_FireRatingProperties - SurfaceSpreadOfFlame: INERT
Type - Pset_ManufacturerOccurrence - BarCode: N/A; SerialNumber: N/A
Type - Pset_ManufacturerTypeInformation - ArticleNumber: RK46; ModelReference: RK46; ModelLabel: RED R 6,3X29; Manufacturer: info@refin.it; ProductionYear: N/A
Type - Pset_PrecastConcreteElementGeneral - SerialNumber: N/A
Type - Pset_ProductRequirements - Name: Upside_Red_6,3X29 R; Category: Pr_35_93_96_19:Ceramic tiles
Type - Pset_QuantityTakeOff - Reference: N/A
Type - Pset_ReinforcementBarPitchOfWall - Description: PORCELAIN STONEWARE TILE; Reference: N/A
Type - Pset_WallCommon - Reference: N/A; IsExternal: no; AcousticRating: N/A; SurfaceSpreadOfFlame: INERT
Type - Pset_Warranty - WarrantyContent: N/A; Exclusions: N/A
Pset_QuantityTakeOff - sets with these values: 2
Pset_WallCommon - LoadBearing: no; ExtendToStructure: no

# IfcWallStandardCase: Basic Wall:Wall_Tiles_Refin-Upside-Red-60x120 RK30, Basic Wall:Wall_Tiles_Refin-Upside-Red-60x120 RK30:354399
In: Level 0
Type - PredefinedType: STANDARD; Material: <Unnamed> 1 mm, Upside-Red-60x120 RK30 9 mm
Type - Pset_ElementShading - Color: RED
Type - Pset_FireRatingProperties - SurfaceSpreadOfFlame: INERT
Type - Pset_ManufacturerOccurrence - BarCode: N/A; SerialNumber: N/A
Type - Pset_ManufacturerTypeInformation - ArticleNumber: RK30; ModelReference: RK30; ModelLabel: RED R 60X120; Manufacturer: info@refin.it; ProductionYear: N/A
Type - Pset_PrecastConcreteElementGeneral - SerialNumber: N/A
Type - Pset_ProductRequirements - Name: Upside_Red_60X120 R; Category: Pr_35_93_96_19:Ceramic tiles
Type - Pset_QuantityTakeOff - Reference: N/A
Type - Pset_ReinforcementBarPitchOfWall - Description: PORCELAIN STONEWARE TILE; Reference: N/A
Type - Pset_WallCommon - Reference: N/A; IsExternal: no; AcousticRating: N/A; SurfaceSpreadOfFlame: INERT
Type - Pset_Warranty - WarrantyContent: N/A; Exclusions: N/A
Pset_QuantityTakeOff - sets with these values: 2
Pset_WallCommon - LoadBearing: no; ExtendToStructure: no

# IfcWallStandardCase: Basic Wall:Wall_Tiles_Refin-Upside-Sky-30x60 RK39, Basic Wall:Wall_Tiles_Refin-Upside-Sky-30x60 RK39:354653
In: Level 0
Type - PredefinedType: STANDARD; Material: <Unnamed> 1 mm, Upside-Sky-30x60 RK39 9 mm
Type - Pset_ElementShading - Color: LIGHT BLUE
Type - Pset_FireRatingProperties - SurfaceSpreadOfFlame: INERT
Type - Pset_ManufacturerOccurrence - BarCode: N/A; SerialNumber: N/A
Type - Pset_ManufacturerTypeInformation - ArticleNumber: RK39; ModelReference: RK39; ModelLabel: SKY R 30X60; Manufacturer: info@refin.it; ProductionYear: N/A
Type - Pset_PrecastConcreteElementGeneral - SerialNumber: N/A
Type - Pset_ProductRequirements - Name: Upside_Sky_30X60 R; Category: Pr_35_93_96_19:Ceramic tiles
Type - Pset_QuantityTakeOff - Reference: N/A
Type - Pset_ReinforcementBarPitchOfWall - Description: PORCELAIN STONEWARE TILE; Reference: N/A
Type - Pset_WallCommon - Reference: N/A; IsExternal: no; AcousticRating: N/A; SurfaceSpreadOfFlame: INERT
Type - Pset_Warranty - WarrantyContent: N/A; Exclusions: N/A
Pset_QuantityTakeOff - sets with these values: 2
Pset_WallCommon - LoadBearing: no; ExtendToStructure: no

# IfcWallStandardCase: Basic Wall:Wall_Tiles_Refin-Upside-Sky-6,3x29 RK47, Basic Wall:Wall_Tiles_Refin-Upside-Sky-6,3x29 RK47:354859
In: Level 0
Type - PredefinedType: STANDARD; Material: <Unnamed> 1 mm, Upside-Sky-6,3x29 RK47 9 mm
Type - Pset_ElementShading - Color: LIGHT BLUE
Type - Pset_FireRatingProperties - SurfaceSpreadOfFlame: INERT
Type - Pset_ManufacturerOccurrence - BarCode: N/A; SerialNumber: N/A
Type - Pset_ManufacturerTypeInformation - ArticleNumber: RK47; ModelReference: RK47; ModelLabel: SKY R 6,3X29; Manufacturer: info@refin.it; ProductionYear: N/A
Type - Pset_PrecastConcreteElementGeneral - SerialNumber: N/A
Type - Pset_ProductRequirements - Name: Upside_Sky_6,3X29 R; Category: Pr_35_93_96_19:Ceramic tiles
Type - Pset_QuantityTakeOff - Reference: N/A
Type - Pset_ReinforcementBarPitchOfWall - Description: PORCELAIN STONEWARE TILE; Reference: N/A
Type - Pset_WallCommon - Reference: N/A; IsExternal: no; AcousticRating: N/A; SurfaceSpreadOfFlame: INERT
Type - Pset_Warranty - WarrantyContent: N/A; Exclusions: N/A
Pset_QuantityTakeOff - sets with these values: 2
Pset_WallCommon - LoadBearing: no; ExtendToStructure: no

# IfcWallStandardCase: Basic Wall:Wall_Tiles_Refin-Upside-Sky-60x120 RK31, Basic Wall:Wall_Tiles_Refin-Upside-Sky-60x120 RK31:354988
In: Level 0
Type - PredefinedType: STANDARD; Material: <Unnamed> 1 mm, Upside-Sky-60x120 RK31 9 mm
Type - Pset_ElementShading - Color: LIGHT BLUE
Type - Pset_FireRatingProperties - SurfaceSpreadOfFlame: INERT
Type - Pset_ManufacturerOccurrence - BarCode: N/A; SerialNumber: N/A
Type - Pset_ManufacturerTypeInformation - ArticleNumber: RK31; ModelReference: RK31; ModelLabel: SKY R 60X120; Manufacturer: info@refin.it; ProductionYear: N/A
Type - Pset_PrecastConcreteElementGeneral - SerialNumber: N/A
Type - Pset_ProductRequirements - Name: Upside_Sky_60X120 R; Category: Pr_35_93_96_19:Ceramic tiles
Type - Pset_QuantityTakeOff - Reference: N/A
Type - Pset_ReinforcementBarPitchOfWall - Description: PORCELAIN STONEWARE TILE; Reference: N/A
Type - Pset_WallCommon - Reference: N/A; IsExternal: no; AcousticRating: N/A; SurfaceSpreadOfFlame: INERT
Type - Pset_Warranty - WarrantyContent: N/A; Exclusions: N/A
Pset_QuantityTakeOff - sets with these values: 2
Pset_WallCommon - LoadBearing: no; ExtendToStructure: no

# IfcWallStandardCase: Basic Wall:Wall_Tiles_Refin-Upside-White-30x60 RK40, Basic Wall:Wall_Tiles_Refin-Upside-White-30x60 RK40:355383
In: Level 0
Type - PredefinedType: STANDARD; Material: <Unnamed> 1 mm, Upside-White-30x60 RK40 9 mm
Type - Pset_ElementShading - Color: WHITE
Type - Pset_FireRatingProperties - SurfaceSpreadOfFlame: INERT
Type - Pset_ManufacturerOccurrence - BarCode: N/A; SerialNumber: N/A
Type - Pset_ManufacturerTypeInformation - ArticleNumber: RK40; ModelReference: RK40; ModelLabel: WHITE R 30X60; Manufacturer: info@refin.it; ProductionYear: N/A
Type - Pset_PrecastConcreteElementGeneral - SerialNumber: N/A
Type - Pset_ProductRequirements - Name: Upside_White_30X60 R; Category: Pr_35_93_96_19:Ceramic tiles
Type - Pset_QuantityTakeOff - Reference: N/A
Type - Pset_ReinforcementBarPitchOfWall - Description: PORCELAIN STONEWARE TILE; Reference: N/A
Type - Pset_WallCommon - Reference: N/A; IsExternal: no; AcousticRating: N/A; SurfaceSpreadOfFlame: INERT
Type - Pset_Warranty - WarrantyContent: N/A; Exclusions: N/A
Pset_QuantityTakeOff - sets with these values: 2
Pset_WallCommon - LoadBearing: no; ExtendToStructure: no

# IfcWallStandardCase: Basic Wall:Wall_Tiles_Refin-Upside-White-6,3x29 RK48, Basic Wall:Wall_Tiles_Refin-Upside-White-6,3x29 RK48:355650
In: Level 0
Type - PredefinedType: STANDARD; Material: <Unnamed> 1 mm, Upside-White-6,3x29 RK48 9 mm
Type - Pset_ElementShading - Color: WHITE
Type - Pset_FireRatingProperties - SurfaceSpreadOfFlame: INERT
Type - Pset_ManufacturerOccurrence - BarCode: N/A; SerialNumber: N/A
Type - Pset_ManufacturerTypeInformation - ArticleNumber: RK48; ModelReference: RK48; ModelLabel: WHITE R 6,3X29; Manufacturer: info@refin.it; ProductionYear: N/A
Type - Pset_PrecastConcreteElementGeneral - SerialNumber: N/A
Type - Pset_ProductRequirements - Name: Upside_White_6,3X29 R; Category: Pr_35_93_96_19:Ceramic tiles
Type - Pset_QuantityTakeOff - Reference: N/A
Type - Pset_ReinforcementBarPitchOfWall - Description: PORCELAIN STONEWARE TILE; Reference: N/A
Type - Pset_WallCommon - Reference: N/A; IsExternal: no; AcousticRating: N/A; SurfaceSpreadOfFlame: INERT
Type - Pset_Warranty - WarrantyContent: N/A; Exclusions: N/A
Pset_QuantityTakeOff - sets with these values: 2
Pset_WallCommon - LoadBearing: no; ExtendToStructure: no

# IfcWallStandardCase: Basic Wall:Wall_Tiles_Refin-Upside-White-60x120 RK32, Basic Wall:Wall_Tiles_Refin-Upside-White-60x120 RK32:355799
In: Level 0
Type - PredefinedType: STANDARD; Material: <Unnamed> 1 mm, Upside-White-60x120 RK32 9 mm
Type - Pset_ElementShading - Color: WHITE
Type - Pset_FireRatingProperties - SurfaceSpreadOfFlame: INERT
Type - Pset_ManufacturerOccurrence - BarCode: N/A; SerialNumber: N/A
Type - Pset_ManufacturerTypeInformation - ArticleNumber: RK32; ModelReference: RK32; ModelLabel: WHITE R 60X120; Manufacturer: info@refin.it; ProductionYear: N/A
Type - Pset_PrecastConcreteElementGeneral - SerialNumber: N/A
Type - Pset_ProductRequirements - Name: Upside_White_60X120 R; Category: Pr_35_93_96_19:Ceramic tiles
Type - Pset_QuantityTakeOff - Reference: N/A
Type - Pset_ReinforcementBarPitchOfWall - Description: PORCELAIN STONEWARE TILE; Reference: N/A
Type - Pset_WallCommon - Reference: N/A; IsExternal: no; AcousticRating: N/A; SurfaceSpreadOfFlame: INERT
Type - Pset_Warranty - WarrantyContent: N/A; Exclusions: N/A
Pset_QuantityTakeOff - sets with these values: 2
Pset_WallCommon - LoadBearing: no; ExtendToStructure: no

# IfcWallStandardCase: Basic Wall:Wall_Tiles_Refin-Upside-Yellow-30x60 RK36, Basic Wall:Wall_Tiles_Refin-Upside-Yellow-30x60 RK36:356295
In: Level 0
Type - PredefinedType: STANDARD; Material: <Unnamed> 1 mm, Upside-Yellow-30x60 RK36 9 mm
Type - Pset_ElementShading - Color: YELLOW
Type - Pset_FireRatingProperties - SurfaceSpreadOfFlame: INERT
Type - Pset_ManufacturerOccurrence - BarCode: N/A; SerialNumber: N/A
Type - Pset_ManufacturerTypeInformation - ArticleNumber: RK36; ModelReference: RK36; ModelLabel: YELLOW R 30X60; Manufacturer: info@refin.it; ProductionYear: N/A
Type - Pset_PrecastConcreteElementGeneral - SerialNumber: N/A
Type - Pset_ProductRequirements - Name: Upside_Yellow_30X60 R; Category: Pr_35_93_96_19:Ceramic tiles
Type - Pset_QuantityTakeOff - Reference: N/A
Type - Pset_ReinforcementBarPitchOfWall - Description: PORCELAIN STONEWARE TILE; Reference: N/A
Type - Pset_WallCommon - Reference: N/A; IsExternal: no; AcousticRating: N/A; SurfaceSpreadOfFlame: INERT
Type - Pset_Warranty - WarrantyContent: N/A; Exclusions: N/A
Pset_QuantityTakeOff - sets with these values: 2
Pset_WallCommon - LoadBearing: no; ExtendToStructure: no

# IfcWallStandardCase: Basic Wall:Wall_Tiles_Refin-Upside-Yellow-6,3x29 RK44, Basic Wall:Wall_Tiles_Refin-Upside-Yellow-6,3x29 RK44:356496
In: Level 0
Type - PredefinedType: STANDARD; Material: <Unnamed> 1 mm, Upside-Yellow-6,3x29 RK44 9 mm
Type - Pset_ElementShading - Color: YELLOW
Type - Pset_FireRatingProperties - SurfaceSpreadOfFlame: INERT
Type - Pset_ManufacturerOccurrence - BarCode: N/A; SerialNumber: N/A
Type - Pset_ManufacturerTypeInformation - ArticleNumber: RK44; ModelReference: RK44; ModelLabel: YELLOW R 6,3X29; Manufacturer: info@refin.it; ProductionYear: N/A
Type - Pset_PrecastConcreteElementGeneral - SerialNumber: N/A
Type - Pset_ProductRequirements - Name: Upside_Yellow_6,3X29 R; Category: Pr_35_93_96_19:Ceramic tiles
Type - Pset_QuantityTakeOff - Reference: N/A
Type - Pset_ReinforcementBarPitchOfWall - Description: PORCELAIN STONEWARE TILE; Reference: N/A
Type - Pset_WallCommon - Reference: N/A; IsExternal: no; AcousticRating: N/A; SurfaceSpreadOfFlame: INERT
Type - Pset_Warranty - WarrantyContent: N/A; Exclusions: N/A
Pset_QuantityTakeOff - sets with these values: 2
Pset_WallCommon - LoadBearing: no; ExtendToStructure: no

# IfcWallStandardCase: Basic Wall:Wall_Tiles_Refin-Upside-Yellow-60x120 RK28, Basic Wall:Wall_Tiles_Refin-Upside-Yellow-60x120 RK28:356693
In: Level 0
Type - PredefinedType: STANDARD; Material: <Unnamed> 1 mm, Upside-Yellow-60x120 RK28 9 mm
Type - Pset_ElementShading - Color: YELLOW
Type - Pset_FireRatingProperties - SurfaceSpreadOfFlame: INERT
Type - Pset_ManufacturerOccurrence - BarCode: N/A; SerialNumber: N/A
Type - Pset_ManufacturerTypeInformation - ArticleNumber: RK28; ModelReference: RK28; ModelLabel: YELLOW R 60X120; Manufacturer: info@refin.it; ProductionYear: N/A
Type - Pset_PrecastConcreteElementGeneral - SerialNumber: N/A
Type - Pset_ProductRequirements - Name: Upside_Yellow_60X120 R; Category: Pr_35_93_96_19:Ceramic tiles
Type - Pset_QuantityTakeOff - Reference: N/A
Type - Pset_ReinforcementBarPitchOfWall - Description: PORCELAIN STONEWARE TILE; Reference: N/A
Type - Pset_WallCommon - Reference: N/A; IsExternal: no; AcousticRating: N/A; SurfaceSpreadOfFlame: INERT
Type - Pset_Warranty - WarrantyContent: N/A; Exclusions: N/A
Pset_QuantityTakeOff - sets with these values: 2
Pset_WallCommon - LoadBearing: no; ExtendToStructure: no
